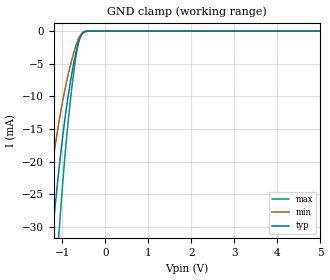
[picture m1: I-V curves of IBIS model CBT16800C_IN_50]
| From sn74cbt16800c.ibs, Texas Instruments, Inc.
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[Model]   CBT16800C_IN_50
Model_type  Input
Vinl=0.8
Vinh=2.0
| variable   typ   min   max
C_comp   4.52pF   2.53pF   8.19pF
[Temperature Range]   40   100   -40
| Ambient temperature   25   85   -40
[Voltage range]   5   4.5   5.5
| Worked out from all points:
|   GND clamp passes 1 mA (typ) near -0.59 V on its own axis
[GND Clamp]
| CBT16800C_IN_50
|   Voltage   I(typ)   I(min)   I(max)
-5V       -417.4mA   -313.8mA   -530.2mA
-1.45V    -47.58mA   -31.24mA   -69.58mA
-1.425V   -45.58mA   -29.9mA    -66.75mA
-1.255V   -32.73mA   -21.4mA    -48.21mA
-1.215V   -29.92mA   -19.56mA   -44.07mA
-1.08V    -21.12mA   -13.88mA   -30.89mA
-910mV    -11.9mA    -7.938mA   -16.81mA
-750mV    -5.384mA   -3.616mA   -6.969mA
-680mV    -3.115mA   -2.099mA   -3.645mA
-615mV    -1.514mA   -1.041mA   -1.461mA
-495mV    -172.7uA   -149.6uA   -80.07uA
5V        220pA      718pA      41.32pA
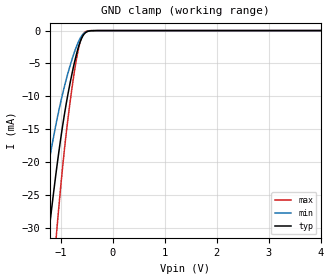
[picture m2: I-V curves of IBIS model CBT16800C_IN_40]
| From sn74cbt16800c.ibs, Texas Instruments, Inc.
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[Model]   CBT16800C_IN_40
Model_type  Input
Vinl=0.8
Vinh=2.0
| variable   typ   min   max
C_comp   3.95pF   2.55pF   6.74pF
[Temperature Range]   40   100   -40
| Ambient temperature   25   85   -40
[Voltage range]   4   4   4
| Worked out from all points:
|   GND clamp passes 1 mA (typ) near -0.59 V on its own axis
[GND Clamp]
| CBT16800C_IN_40
|   Voltage   I(typ)   I(min)   I(max)
-4V       -307.4mA   -226mA     -397.7mA
-1.435V   -46.38mA   -30.43mA   -67.88mA
-1.24V    -31.66mA   -20.7mA    -46.65mA
-1.205V   -29.23mA   -19.12mA   -43.05mA
-1.08V    -21.12mA   -13.88mA   -30.89mA
-910mV    -11.9mA    -7.938mA   -16.81mA
-755mV    -5.562mA   -3.735mA   -7.234mA
-695mV    -3.56mA    -2.396mA   -4.286mA
-635mV    -1.944mA   -1.323mA   -2.02mA
-580mV    -909.9uA   -647.5uA   -742.7uA
-515mV    -268.8uA   -219.5uA   -144.4uA
4V        162.4pA    581.9pA    36.11pA
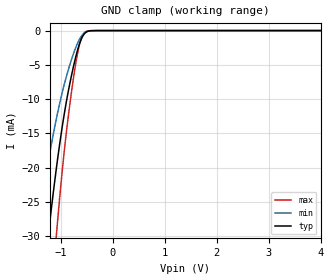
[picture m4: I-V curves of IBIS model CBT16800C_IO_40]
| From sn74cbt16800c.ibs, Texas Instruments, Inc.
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[Model]   CBT16800C_IO_40
Model_type  Terminator
| variable   typ   min   max
C_comp   5.81pF   4.37pF   8.51pF
| C_tri-state   5.81pF   4.37pF   8.51pF
[Temperature Range]   40   100   -40
| Ambient temperature   25   85   -40
[Voltage range]   4   4   4
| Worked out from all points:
|   GND clamp passes 1 mA (typ) near -0.59 V on its own axis
[GND Clamp]
| CBT16800C_IO_40
|   Voltage   I(typ)   I(min)   I(max)
-4V       -295.9mA   -216.2mA   -383.9mA
-1.455V   -45.58mA   -29.39mA   -67.35mA
-1.24V    -29.96mA   -19.17mA   -44.71mA
-1.205V   -27.63mA   -17.67mA   -41.25mA
-1.08V    -19.92mA   -12.76mA   -29.58mA
-910mV    -11.21mA   -7.242mA   -16.12mA
-755mV    -5.273mA   -3.395mA   -6.972mA
-695mV    -3.395mA   -2.188mA   -4.131mA
-635mV    -1.864mA   -1.225mA   -1.947mA
-580mV    -875.1uA   -611.9uA   -715.7uA
-515mV    -258.9uA   -210.2uA   -139.2uA
4V        419.1pA    1.536nA    95.05pA
